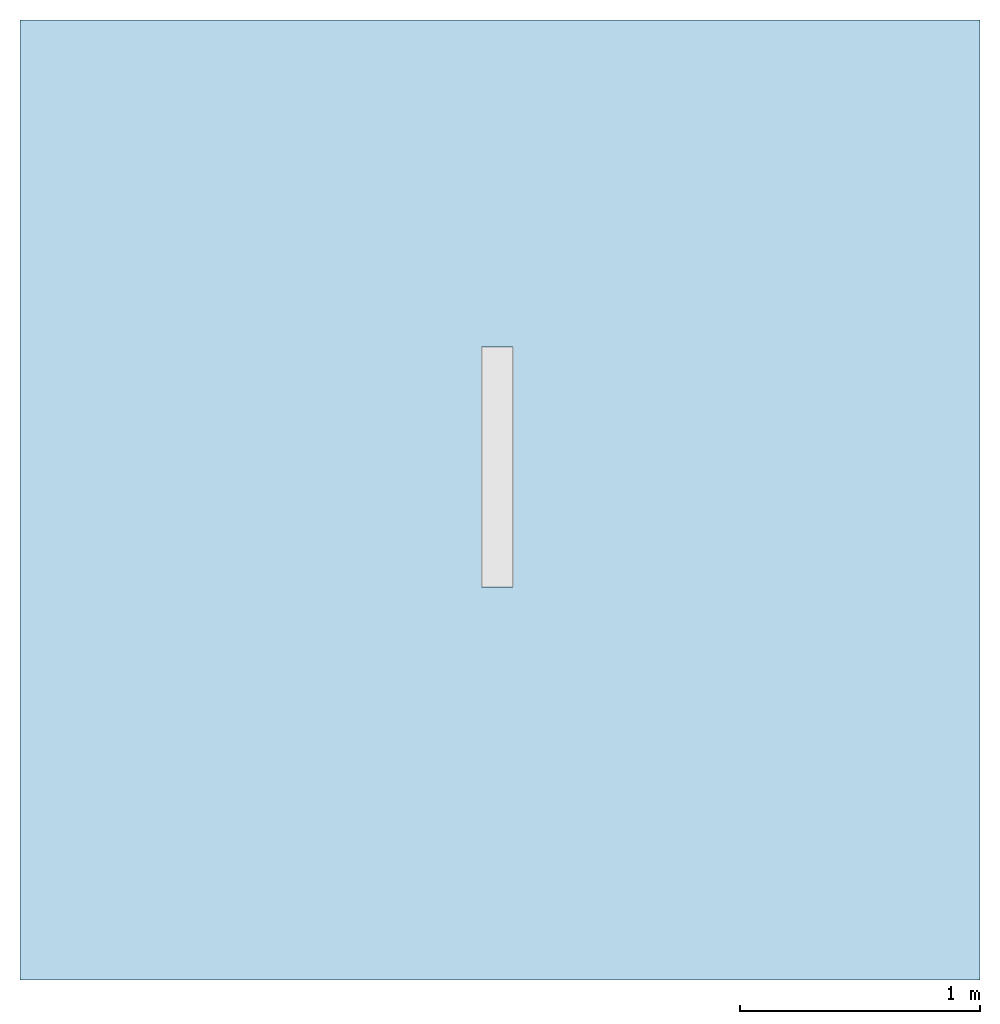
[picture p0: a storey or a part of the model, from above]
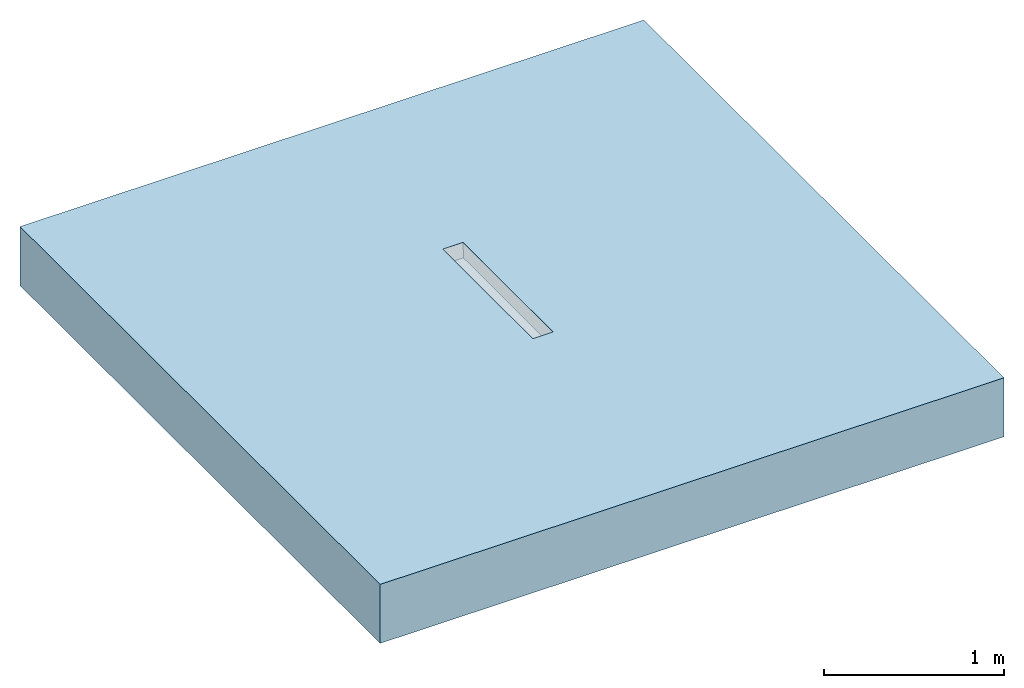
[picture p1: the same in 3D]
Properties of the parts of a building model (IFC2X3)

# File
Description: ViewDefinition [CoordinationView]
File name: Project Number
Time: 2014-06-06T14:14:48
Written by: The EXPRESS Data Manager Version 5.01.0100.02.64mod : 6 Jun 2012
Made in: 20130308_1515(x64) - Exporter 2014.0.2013.0308 - Default UI
Comment: STEP Physical File produced by: The EXPRESS Data Manager Version 5.01.0100.02.64mod : 6 Jun 2012 * Module: EDMstepFileFactory/EDMstandAlone * Creation date: Fri Jun 06 14:14:48 2014 * Host: IN-BLR-PC-0010 * Database: C:\Users\palleri\AppData\Local\Temp\{4C3BE154-13A0-4F0F-AD0B-4F7AC4DC4BA0}\ifc * Database version: 5507 * Database creation date: Fri Jun 06 14:14:46 2014 * Schema: IFC2X3 * Model: DataRepository.ifc * Model creation date: Fri Jun 06 14:14:47 2014 * Header model: DataRepository.ifc_HeaderModel * Header model creation date: Fri Jun 06 14:14:47 2014 * EDMuser: sdai-user * EDMgroup: sdai-group * License ID and type: 5605 : Permanent license. Expiry date: * EDMstepFileFactory options: 020000

# IfcProject, Project Number
LongName: Project Name; Phase: Project Status

# IfcSite, Default
RefLatitude: 42, 21, 30, 344238; RefLongitude: -71, -3, -35, -194702; RefElevation: 0 mm

# IfcBuilding
Pset_BuildingCommon - NumberOfStoreys: 1
Other - Project Number: Project Number; Project Issue Date: Issue Date; Project Status: Project Status; Project Name: Project Name; Project Address: ## Street City, State Zip; Client Name: Owner

# IfcBuildingStorey, Level 1
LongName: Level 1; Elevation: 0 mm
Constraints - Elevation Base: Project Base Point; Elevation: 0 mm
Graphics - Symbol at End 2 Default: yes; Symbol at End 1 Default: no; Line Weight: 1; Color: 0; Line Pattern: Center; Symbol: M_Level Head - Circle: M_Level Head - Circle
Identity Data - Building Story: yes; Name: Level 1; Structural: no
Dimensions - Computation Height: 0 mm

# IfcFlowTerminal: 36788 - Adjustable Channel - Intermediate Section - 1000mm LG - Invert Depth 75/105mm, ACO Freedeck Adjustable Height Channel Intermediate Section Galvanized Steel:36788 - Adjustable Channel - Intermediate Section - 1000mm LG - Invert Depth 75/105mm:309511
In: Level 1
Material: Galvanized Steel
Construction - 00276 - Grating - Slotted Grating - Galvanised Steel - 1000mm long: no; End Plate Invert 1: no; 00277 - Grating - Slotted Grating - Galvanised Steel - 500mm long: no; 36952 - Grating - Plain Mesh - Galvanised Steel - 500mm long: yes; 36953 - Grating - Plain Mesh - Galvanised Steel - 1000mm long: no; End Plate Invert 2: no
Other - Top Piece Void Height @ Invert 2: 45 mm; Height @ Invert 2 Min & Max: 105 mm; Top Piece Void Height @ Invert 1: 45 mm; Height @ Invert 1 Min & Max: 105 mm; Nos: 32
Identity Data - Mark: 28; Watermarked By: www.acobd.com; Watermark1: This file is the property of ACO Technologies PLC; Website: www.acobd.com; Watermarked With: BIM Manager Premium Suite; Manufacturer: ACO Building Drainage; Watermark2: This file is water marked and users are prohibited to reproduce, adapt, distribute this information; Address: ACO Business Centre, Caxton Road, Bedford, MK41 0LF; Telephone: +44 (0)1462 816666; E-mail Sales: abdcommercial@aco.co.uk; Fax: +44 (0)1462 851490; E-mail Technical: abdtechnical@aco.co.uk
Constraints - Moves With Nearby Elements: no; Level: Level: Level 1
Phasing - Phase Created: New Construction
Dimensions - Height @ Invert 1 (75 - 105mm): 105 mm; Height @ Invert 2 (75 - 105mm): 105 mm; Grating End Length: 1000 mm; Channel End Length: -1000 mm
Pset_ManufacturerTypeInformation - Manufacturer: ACO Building Drainage
General - Product Code: 36788; NBS Specification: NBS Section R10 Gravity Rainwater Drainage Systems, Subsection 365; Dimensions (LxWxH): 1000 x 130 x 75/105; Load Class: A15; Price: POA - contact ACO; Maintenance Guidelines: X:\Electronic Literature\ABD Electronic Literature\Roof and Balcony Drainage\ACO Freedeck Brochure.pdf; Channel Material: Hot Dipped Galvanised Steel; Product Range: ACO Freedeck; Channel Recyclable: Fully recyclable; Channel Recycled Material Content: 25 - 30 %; Installation Guidelines: X:\Electronic Literature\ABD Electronic Literature\Roof and Balcony Drainage\ACO Freedeck Brochure.pdf; Product Description: ACO Freedeck Adjustable Channel - Intermediate Section; Weight (Kg): 5.4kg; Product Standard: BS EN 1433:2002, CE marked; Channel Colour: Galvanised; Product Type: Linear Deck Drainage System
Materials and Finishes - Material: Galvanized Steel
Model Properties - Grating Product Code 36952: Load Class A15 - Mesh Grating - 14mm x 30mm Mesh - Galvanized Steel - 500mm long - 1.6kg; Grating Product Code 00277: Load Class A15 - Slotted Grating - 10 x 80mm Slot - Galvanized Steel - 500mm long - 1.0kg; End Plate Product Code 36793: End Plate Galvanized Steel for Invert Depth - 75/105mm - 0.1Kg; Grating Product Code 00276: Load Class A15 - Slotted Grating - 10 x 80mm Slot - Galvanized Steel - 1000mm long - 2.2kg; Grating Product Code 36953: Load Class A15 - Mesh Grating - 14mm x 30mm Mesh - Galvanized Steel - 1000mm long - 3.0kg

# IfcOpeningElement: Recess
In: Level 1
Dimensions - Area: 16 m2; Thickness: 400 mm; Perimeter: 16000 mm; Volume: 6.38611 m3
Constraints - Height Offset From Level: 0 mm; Room Bounding: yes; Related to Mass: no; Level: Level: Level 1
Phasing - Phase Created: New Construction
Structural - Enable Analytical Model: no; Structural: no
Construction - Function: Interior; Default Thickness: 400 mm
Analytical Properties - Roughness: 1; Thermal mass: 604440; Heat Transfer Coefficient (U): 2.615; Absorptance: 0.1; Thermal Resistance (R): 0.382409
Graphics - Coarse Scale Fill Color: 0
Materials and Finishes - Structural Material: Concrete, Broom Finish

# IfcSlab: Floor:Generic Floor - 400mm, Floor:Generic Floor - 400mm:193825
In: Level 1
PredefinedType: FLOOR; Material: Concrete, Broom Finish 400 mm
Dimensions - Area: 16 m2; Thickness: 400 mm; Perimeter: 16000 mm; Volume: 6.38611 m3
Constraints - Height Offset From Level: 0 mm; Room Bounding: yes; Related to Mass: no; Level: Level: Level 1
Phasing - Phase Created: New Construction
Structural - Enable Analytical Model: no; Structural: no
Pset_SlabCommon - Reference: Generic Floor - 400mm; IsExternal: no; LoadBearing: yes; ThermalTransmittance: 2.615 kg/K/s3
Construction - Function: Interior; Default Thickness: 400 mm
Analytical Properties - Roughness: 1; Thermal mass: 604440; Heat Transfer Coefficient (U): 2.615; Absorptance: 0.1; Thermal Resistance (R): 0.382409
Graphics - Coarse Scale Fill Color: 0
Materials and Finishes - Structural Material: Concrete, Broom Finish
